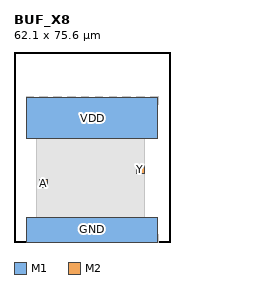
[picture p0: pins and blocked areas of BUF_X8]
MACRO BUF_X8
  CLASS CORE ;
  ORIGIN 0 0 ;
  SIZE 62.100 BY 75.600 ;
  SYMMETRY X Y ;
  SITE TR1um_access_site ;
  PIN VDD
    DIRECTION INOUT ;
    USE POWER ;
    PORT
      LAYER M1 ;
        RECT 5.000 41.000 57.100 57.600 ;
    END
  END VDD
  PIN GND
    DIRECTION INOUT ;
    USE GROUND ;
    PORT
      LAYER M1 ;
        RECT 5.000 0.000 57.100 9.800 ;
    END
  END GND
  PIN A
    DIRECTION INPUT ;
    USE SIGNAL ;
    PORT
      LAYER M2 ;
        RECT 10.100 21.600 13.500 25.000 ;
    END
  END A
  PIN Y
    DIRECTION OUTPUT ;
    USE SIGNAL ;
    PORT
      LAYER M2 ;
        RECT 48.600 27.100 52.000 30.500 ;
    END
  END Y
  OBS
    LAYER M1 ;
      RECT 10.100 21.600 16.900 25.000 ;
    LAYER M1 ;
      RECT 13.100 6.400 42.500 51.200 ;
    LAYER M1 ;
      RECT 21.100 6.400 52.000 51.200 ;
    LAYER V1 ;
      RECT 4.800 0.000 7.800 2.800 ;
    LAYER V1 ;
      RECT 10.300 0.000 13.300 2.800 ;
    LAYER V1 ;
      RECT 15.800 0.000 18.800 2.800 ;
    LAYER V1 ;
      RECT 21.300 0.000 24.300 2.800 ;
    LAYER V1 ;
      RECT 26.800 0.000 29.800 2.800 ;
    LAYER V1 ;
      RECT 32.300 0.000 35.300 2.800 ;
    LAYER V1 ;
      RECT 37.800 0.000 40.800 2.800 ;
    LAYER V1 ;
      RECT 43.300 0.000 46.300 2.800 ;
    LAYER V1 ;
      RECT 48.800 0.000 51.800 2.800 ;
    LAYER V1 ;
      RECT 54.300 0.000 57.300 2.800 ;
    LAYER V1 ;
      RECT 11.100 22.600 12.500 24.000 ;
    LAYER V1 ;
      RECT 49.600 28.100 51.000 29.500 ;
    LAYER V1 ;
      RECT 8.900 4.000 51.900 53.600 ;
    LAYER V1 ;
      RECT 4.800 54.800 7.800 57.800 ;
    LAYER V1 ;
      RECT 10.300 54.800 13.300 57.800 ;
    LAYER V1 ;
      RECT 15.800 54.800 18.800 57.800 ;
    LAYER V1 ;
      RECT 21.300 54.800 24.300 57.800 ;
    LAYER V1 ;
      RECT 26.800 54.800 29.800 57.800 ;
    LAYER V1 ;
      RECT 32.300 54.800 35.300 57.800 ;
    LAYER V1 ;
      RECT 37.800 54.800 40.800 57.800 ;
    LAYER V1 ;
      RECT 43.300 54.800 46.300 57.800 ;
    LAYER V1 ;
      RECT 48.800 54.800 51.800 57.800 ;
    LAYER V1 ;
      RECT 54.300 54.800 57.300 57.800 ;
  END
END BUF_X8
